VERSION 5.4 ;
NAMESCASESENSITIVE ON ;
BUSBITCHARS "[]" ;
DIVIDERCHAR "/" ;
UNITS
  DATABASE MICRONS 2000 ;
END UNITS
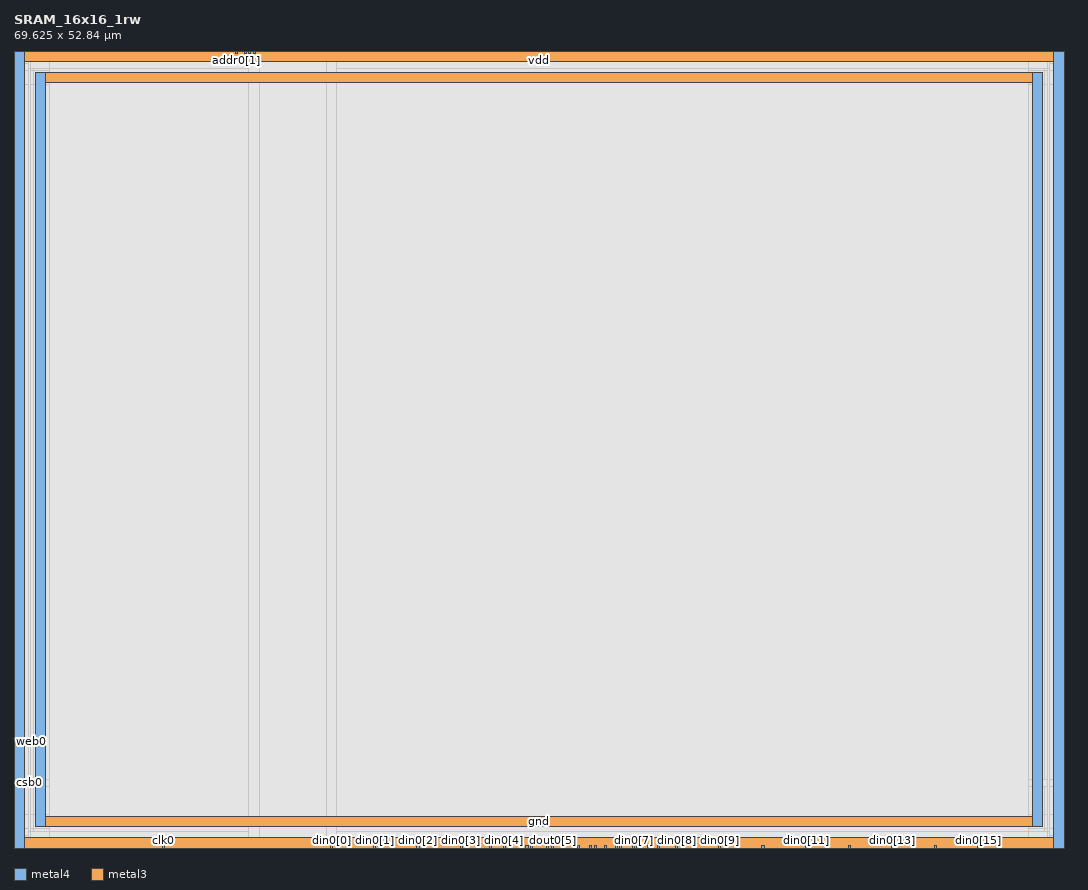
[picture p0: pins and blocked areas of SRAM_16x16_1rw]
MACRO SRAM_16x16_1rw
   CLASS BLOCK ;
   SIZE 69.625 BY 52.84 ;
   SYMMETRY X Y R90 ;
   PIN din0[0]
      DIRECTION INPUT ;
      PORT
         LAYER metal4 ;
         RECT  20.9975 0.0 21.1375 0.14 ;
      END
   END din0[0]
   PIN din0[1]
      DIRECTION INPUT ;
      PORT
         LAYER metal4 ;
         RECT  23.8575 0.0 23.9975 0.14 ;
      END
   END din0[1]
   PIN din0[2]
      DIRECTION INPUT ;
      PORT
         LAYER metal4 ;
         RECT  26.7175 0.0 26.8575 0.14 ;
      END
   END din0[2]
   PIN din0[3]
      DIRECTION INPUT ;
      PORT
         LAYER metal4 ;
         RECT  29.5775 0.0 29.7175 0.14 ;
      END
   END din0[3]
   PIN din0[4]
      DIRECTION INPUT ;
      PORT
         LAYER metal4 ;
         RECT  32.4375 0.0 32.5775 0.14 ;
      END
   END din0[4]
   PIN din0[5]
      DIRECTION INPUT ;
      PORT
         LAYER metal4 ;
         RECT  35.2975 0.0 35.4375 0.14 ;
      END
   END din0[5]
   PIN din0[6]
      DIRECTION INPUT ;
      PORT
         LAYER metal4 ;
         RECT  38.1575 0.0 38.2975 0.14 ;
      END
   END din0[6]
   PIN din0[7]
      DIRECTION INPUT ;
      PORT
         LAYER metal4 ;
         RECT  41.0175 0.0 41.1575 0.14 ;
      END
   END din0[7]
   PIN din0[8]
      DIRECTION INPUT ;
      PORT
         LAYER metal4 ;
         RECT  43.8775 0.0 44.0175 0.14 ;
      END
   END din0[8]
   PIN din0[9]
      DIRECTION INPUT ;
      PORT
         LAYER metal4 ;
         RECT  46.7375 0.0 46.8775 0.14 ;
      END
   END din0[9]
   PIN din0[10]
      DIRECTION INPUT ;
      PORT
         LAYER metal4 ;
         RECT  49.5975 0.0 49.7375 0.14 ;
      END
   END din0[10]
   PIN din0[11]
      DIRECTION INPUT ;
      PORT
         LAYER metal4 ;
         RECT  52.4575 0.0 52.5975 0.14 ;
      END
   END din0[11]
   PIN din0[12]
      DIRECTION INPUT ;
      PORT
         LAYER metal4 ;
         RECT  55.3175 0.0 55.4575 0.14 ;
      END
   END din0[12]
   PIN din0[13]
      DIRECTION INPUT ;
      PORT
         LAYER metal4 ;
         RECT  58.1775 0.0 58.3175 0.14 ;
      END
   END din0[13]
   PIN din0[14]
      DIRECTION INPUT ;
      PORT
         LAYER metal4 ;
         RECT  61.0375 0.0 61.1775 0.14 ;
      END
   END din0[14]
   PIN din0[15]
      DIRECTION INPUT ;
      PORT
         LAYER metal4 ;
         RECT  63.8975 0.0 64.0375 0.14 ;
      END
   END din0[15]
   PIN addr0[0]
      DIRECTION INPUT ;
      PORT
         LAYER metal4 ;
         RECT  15.85 52.7 15.99 52.84 ;
      END
   END addr0[0]
   PIN addr0[1]
      DIRECTION INPUT ;
      PORT
         LAYER metal4 ;
         RECT  14.71 52.7 14.85 52.84 ;
      END
   END addr0[1]
   PIN addr0[2]
      DIRECTION INPUT ;
      PORT
         LAYER metal4 ;
         RECT  15.565 52.7 15.705 52.84 ;
      END
   END addr0[2]
   PIN addr0[3]
      DIRECTION INPUT ;
      PORT
         LAYER metal4 ;
         RECT  15.28 52.7 15.42 52.84 ;
      END
   END addr0[3]
   PIN csb0
      DIRECTION INPUT ;
      PORT
         LAYER metal3 ;
         RECT  0.0 4.25 0.14 4.39 ;
      END
   END csb0
   PIN web0
      DIRECTION INPUT ;
      PORT
         LAYER metal3 ;
         RECT  0.0 6.98 0.14 7.12 ;
      END
   END web0
   PIN clk0
      DIRECTION INPUT ;
      PORT
         LAYER metal4 ;
         RECT  9.84 0.0 9.98 0.14 ;
      END
   END clk0
   PIN dout0[0]
      DIRECTION OUTPUT ;
      PORT
         LAYER metal4 ;
         RECT  31.5475 0.0 31.6875 0.14 ;
      END
   END dout0[0]
   PIN dout0[1]
      DIRECTION OUTPUT ;
      PORT
         LAYER metal4 ;
         RECT  32.825 0.0 32.965 0.14 ;
      END
   END dout0[1]
   PIN dout0[2]
      DIRECTION OUTPUT ;
      PORT
         LAYER metal4 ;
         RECT  33.53 0.0 33.67 0.14 ;
      END
   END dout0[2]
   PIN dout0[3]
      DIRECTION OUTPUT ;
      PORT
         LAYER metal4 ;
         RECT  34.235 0.0 34.375 0.14 ;
      END
   END dout0[3]
   PIN dout0[4]
      DIRECTION OUTPUT ;
      PORT
         LAYER metal4 ;
         RECT  33.95 0.0 34.09 0.14 ;
      END
   END dout0[4]
   PIN dout0[5]
      DIRECTION OUTPUT ;
      PORT
         LAYER metal4 ;
         RECT  35.645 0.0 35.785 0.14 ;
      END
   END dout0[5]
   PIN dout0[6]
      DIRECTION OUTPUT ;
      PORT
         LAYER metal4 ;
         RECT  36.35 0.0 36.49 0.14 ;
      END
   END dout0[6]
   PIN dout0[7]
      DIRECTION OUTPUT ;
      PORT
         LAYER metal4 ;
         RECT  37.055 0.0 37.195 0.14 ;
      END
   END dout0[7]
   PIN dout0[8]
      DIRECTION OUTPUT ;
      PORT
         LAYER metal4 ;
         RECT  37.34 0.0 37.48 0.14 ;
      END
   END dout0[8]
   PIN dout0[9]
      DIRECTION OUTPUT ;
      PORT
         LAYER metal4 ;
         RECT  38.465 0.0 38.605 0.14 ;
      END
   END dout0[9]
   PIN dout0[10]
      DIRECTION OUTPUT ;
      PORT
         LAYER metal4 ;
         RECT  39.17 0.0 39.31 0.14 ;
      END
   END dout0[10]
   PIN dout0[11]
      DIRECTION OUTPUT ;
      PORT
         LAYER metal4 ;
         RECT  39.875 0.0 40.015 0.14 ;
      END
   END dout0[11]
   PIN dout0[12]
      DIRECTION OUTPUT ;
      PORT
         LAYER metal4 ;
         RECT  40.16 0.0 40.3 0.14 ;
      END
   END dout0[12]
   PIN dout0[13]
      DIRECTION OUTPUT ;
      PORT
         LAYER metal4 ;
         RECT  41.3025 0.0 41.4425 0.14 ;
      END
   END dout0[13]
   PIN dout0[14]
      DIRECTION OUTPUT ;
      PORT
         LAYER metal4 ;
         RECT  41.99 0.0 42.13 0.14 ;
      END
   END dout0[14]
   PIN dout0[15]
      DIRECTION OUTPUT ;
      PORT
         LAYER metal4 ;
         RECT  42.695 0.0 42.835 0.14 ;
      END
   END dout0[15]
   PIN vdd
      DIRECTION INOUT ;
      USE POWER ; 
      SHAPE ABUTMENT ; 
      PORT
         LAYER metal3 ;
         RECT  0.0 52.14 69.625 52.84 ;
         LAYER metal3 ;
         RECT  0.0 0.0 69.625 0.7 ;
         LAYER metal4 ;
         RECT  68.925 0.0 69.625 52.84 ;
         LAYER metal4 ;
         RECT  0.0 0.0 0.7 52.84 ;
      END
   END vdd
   PIN gnd
      DIRECTION INOUT ;
      USE GROUND ; 
      SHAPE ABUTMENT ; 
      PORT
         LAYER metal3 ;
         RECT  1.4 50.74 68.225 51.44 ;
         LAYER metal3 ;
         RECT  1.4 1.4 68.225 2.1 ;
         LAYER metal4 ;
         RECT  67.525 1.4 68.225 51.44 ;
         LAYER metal4 ;
         RECT  1.4 1.4 2.1 51.44 ;
      END
   END gnd
   OBS
   LAYER  metal1 ;
      RECT  0.14 0.14 69.485 52.7 ;
   LAYER  metal2 ;
      RECT  0.14 0.14 69.485 52.7 ;
   LAYER  metal3 ;
      RECT  0.28 4.11 69.485 4.53 ;
      RECT  0.14 4.53 0.28 6.84 ;
      RECT  0.14 7.26 0.28 52.0 ;
      RECT  0.14 0.84 0.28 4.11 ;
      RECT  0.28 4.53 1.26 50.6 ;
      RECT  0.28 50.6 1.26 51.58 ;
      RECT  0.28 51.58 1.26 52.0 ;
      RECT  1.26 4.53 68.365 50.6 ;
      RECT  1.26 51.58 68.365 52.0 ;
      RECT  68.365 4.53 69.485 50.6 ;
      RECT  68.365 50.6 69.485 51.58 ;
      RECT  68.365 51.58 69.485 52.0 ;
      RECT  0.28 0.84 1.26 1.26 ;
      RECT  0.28 1.26 1.26 2.24 ;
      RECT  0.28 2.24 1.26 4.11 ;
      RECT  1.26 0.84 68.365 1.26 ;
      RECT  1.26 2.24 68.365 4.11 ;
      RECT  68.365 0.84 69.485 1.26 ;
      RECT  68.365 1.26 69.485 2.24 ;
      RECT  68.365 2.24 69.485 4.11 ;
   LAYER  metal4 ;
      RECT  20.7175 0.42 21.4175 52.7 ;
      RECT  21.4175 0.14 23.5775 0.42 ;
      RECT  24.2775 0.14 26.4375 0.42 ;
      RECT  27.1375 0.14 29.2975 0.42 ;
      RECT  44.2975 0.14 46.4575 0.42 ;
      RECT  47.1575 0.14 49.3175 0.42 ;
      RECT  50.0175 0.14 52.1775 0.42 ;
      RECT  52.8775 0.14 55.0375 0.42 ;
      RECT  55.7375 0.14 57.8975 0.42 ;
      RECT  58.5975 0.14 60.7575 0.42 ;
      RECT  61.4575 0.14 63.6175 0.42 ;
      RECT  15.57 0.42 16.27 52.42 ;
      RECT  16.27 0.42 20.7175 52.42 ;
      RECT  16.27 52.42 20.7175 52.7 ;
      RECT  10.26 0.14 20.7175 0.42 ;
      RECT  29.9975 0.14 31.2675 0.42 ;
      RECT  31.9675 0.14 32.1575 0.42 ;
      RECT  33.245 0.14 33.25 0.42 ;
      RECT  34.655 0.14 35.0175 0.42 ;
      RECT  36.065 0.14 36.07 0.42 ;
      RECT  36.77 0.14 36.775 0.42 ;
      RECT  37.76 0.14 37.8775 0.42 ;
      RECT  38.885 0.14 38.89 0.42 ;
      RECT  39.59 0.14 39.595 0.42 ;
      RECT  40.58 0.14 40.7375 0.42 ;
      RECT  42.41 0.14 42.415 0.42 ;
      RECT  43.115 0.14 43.5975 0.42 ;
      RECT  64.3175 0.14 68.645 0.42 ;
      RECT  0.98 52.42 14.43 52.7 ;
      RECT  0.98 0.14 9.56 0.42 ;
      RECT  21.4175 0.42 67.245 1.12 ;
      RECT  21.4175 1.12 67.245 51.72 ;
      RECT  21.4175 51.72 67.245 52.7 ;
      RECT  67.245 0.42 68.505 1.12 ;
      RECT  67.245 51.72 68.505 52.7 ;
      RECT  68.505 0.42 68.645 1.12 ;
      RECT  68.505 1.12 68.645 51.72 ;
      RECT  68.505 51.72 68.645 52.7 ;
      RECT  0.98 0.42 1.12 1.12 ;
      RECT  0.98 1.12 1.12 51.72 ;
      RECT  0.98 51.72 1.12 52.42 ;
      RECT  1.12 0.42 2.38 1.12 ;
      RECT  1.12 51.72 2.38 52.42 ;
      RECT  2.38 0.42 15.57 1.12 ;
      RECT  2.38 1.12 15.57 51.72 ;
      RECT  2.38 51.72 15.57 52.42 ;
   END
END    SRAM_16x16_1rw
END    LIBRARY
